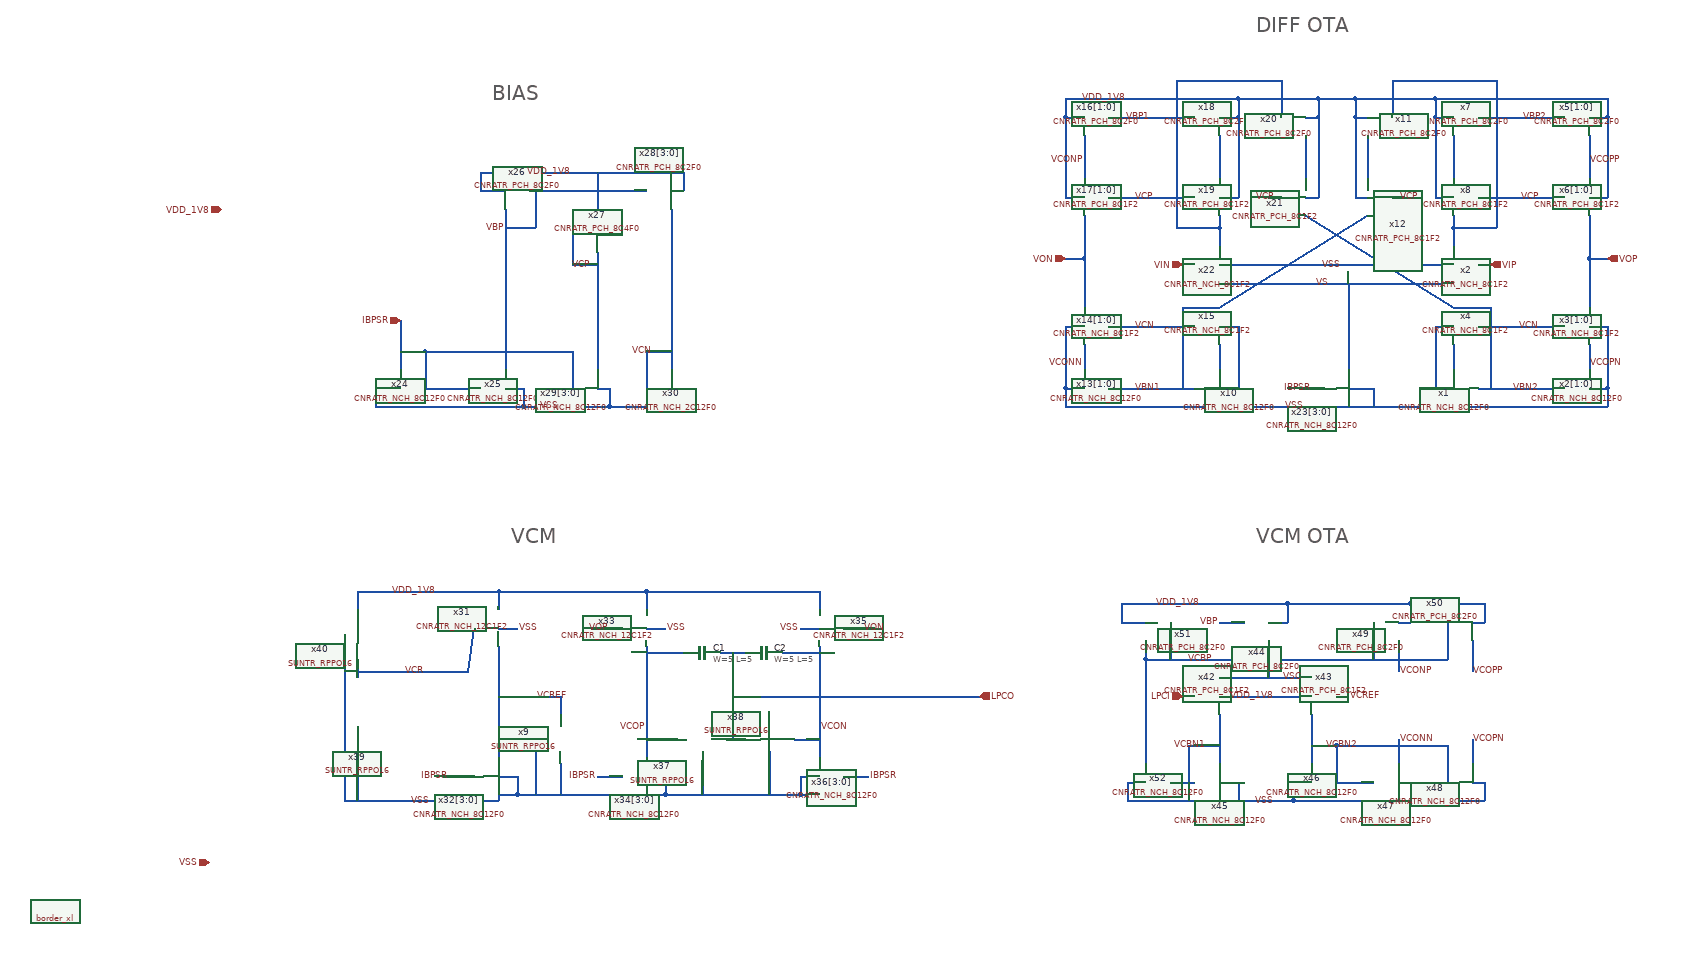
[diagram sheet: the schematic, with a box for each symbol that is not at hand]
v {xschem version=3.4.4 file_version=1.2
}
G {}
K {}
V {}
S {}
E {}
T {DIFF OTA} 1830 -1450 0 0 1 1 {}
T {BIAS} 590 -1340 0 0 1 1 {}
T {VCM} 620 -620 0 0 1 1 {}
T {VCM OTA} 1830 -620 0 0 1 1 {}
N 2120 -1290 2150 -1290 {
lab=VDD_1V8}
N 2120 -1320 2120 -1290 {
lab=VDD_1V8}
N 2120 -1320 2150 -1320 {
lab=VDD_1V8}
N 2370 -1290 2400 -1290 {
lab=VDD_1V8}
N 2400 -1320 2400 -1290 {
lab=VDD_1V8}
N 2370 -1320 2400 -1320 {
lab=VDD_1V8}
N 2370 -1260 2370 -1190 {
lab=VCOPP}
N 2150 -1260 2150 -1190 {
lab=#net1}
N 2120 -1160 2150 -1160 {
lab=VDD_1V8}
N 2120 -1290 2120 -1160 {
lab=VDD_1V8}
N 2370 -1160 2400 -1160 {
lab=VDD_1V8}
N 2400 -1290 2400 -1160 {
lab=VDD_1V8}
N 2150 -920 2150 -880 {
lab=#net2}
N 2120 -950 2150 -950 {
lab=VSS}
N 2120 -950 2120 -820 {
lab=VSS}
N 2120 -820 2150 -820 {
lab=VSS}
N 2120 -850 2150 -850 {
lab=VSS}
N 2370 -850 2400 -850 {
lab=VSS}
N 2400 -850 2400 -820 {
lab=VSS}
N 2370 -820 2400 -820 {
lab=VSS}
N 2370 -920 2370 -880 {
lab=VCOPN}
N 2370 -950 2400 -950 {
lab=VSS}
N 2400 -950 2400 -850 {
lab=VSS}
N 2150 -1320 2370 -1320 {
lab=VDD_1V8}
N 2190 -850 2330 -850 {
lab=VBN2}
N 2190 -1290 2330 -1290 {
lab=VBP2}
N 2150 -1130 2150 -1110 {
lab=VBP2}
N 2150 -980 2210 -980 {
lab=VBN2}
N 2210 -980 2210 -850 {
lab=VBN2}
N 2150 -820 2370 -820 {
lab=VSS}
N 2010 -1320 2120 -1320 {
lab=VDD_1V8}
N 1990 -1320 2010 -1320 {
lab=VDD_1V8}
N 1990 -1320 1990 -1290 {
lab=VDD_1V8}
N 1990 -1290 2010 -1290 {
lab=VDD_1V8}
N 1990 -1290 1990 -1160 {
lab=VDD_1V8}
N 1990 -1160 2010 -1160 {
lab=VDD_1V8}
N 2010 -1260 2010 -1190 {
lab=#net3}
N 2190 -1160 2330 -1160 {
lab=VCP}
N 2190 -950 2330 -950 {
lab=VCN}
N 1990 -820 2010 -820 {
lab=VSS}
N 2150 -1110 2150 -1080 {
lab=VBP2}
N 2010 -820 2120 -820 {
lab=VSS}
N 2220 -1290 2220 -1230 {
lab=VBP2}
N 2220 -1230 2220 -1110 {
lab=VBP2}
N 2150 -1110 2220 -1110 {
lab=VBP2}
N 2050 -1350 2050 -1290 {
lab=VBP2}
N 2050 -1350 2220 -1350 {
lab=VBP2}
N 2220 -1350 2220 -1290 {
lab=VBP2}
N 2050 -1160 2070 -1160 {
lab=VCP}
N 1990 -1020 2150 -1020 {
lab=VS}
N 1770 -1290 1800 -1290 {
lab=VDD_1V8}
N 1800 -1320 1800 -1290 {
lab=VDD_1V8}
N 1770 -1320 1800 -1320 {
lab=VDD_1V8}
N 1520 -1290 1550 -1290 {
lab=VDD_1V8}
N 1520 -1320 1520 -1290 {
lab=VDD_1V8}
N 1520 -1320 1550 -1320 {
lab=VDD_1V8}
N 1550 -1260 1550 -1190 {
lab=VCONP}
N 1770 -1260 1770 -1190 {
lab=#net4}
N 1770 -1160 1800 -1160 {
lab=VDD_1V8}
N 1800 -1290 1800 -1160 {
lab=VDD_1V8}
N 1520 -1160 1550 -1160 {
lab=VDD_1V8}
N 1520 -1290 1520 -1160 {
lab=VDD_1V8}
N 1770 -920 1770 -880 {
lab=#net5}
N 1770 -950 1800 -950 {
lab=VSS}
N 1800 -950 1800 -820 {
lab=VSS}
N 1770 -820 1800 -820 {
lab=VSS}
N 1770 -850 1800 -850 {
lab=VSS}
N 1520 -850 1550 -850 {
lab=VSS}
N 1520 -850 1520 -820 {
lab=VSS}
N 1520 -820 1550 -820 {
lab=VSS}
N 1550 -920 1550 -880 {
lab=VCONN}
N 1520 -950 1550 -950 {
lab=VSS}
N 1520 -950 1520 -850 {
lab=VSS}
N 1550 -1320 1770 -1320 {
lab=VDD_1V8}
N 1590 -850 1730 -850 {
lab=VBN1}
N 1590 -1290 1730 -1290 {
lab=VBP1}
N 1770 -1130 1770 -1110 {
lab=VBP1}
N 1710 -980 1770 -980 {
lab=VBN1}
N 1710 -980 1710 -850 {
lab=VBN1}
N 1550 -820 1770 -820 {
lab=VSS}
N 1800 -1320 1910 -1320 {
lab=VDD_1V8}
N 1910 -1320 1930 -1320 {
lab=VDD_1V8}
N 1930 -1320 1930 -1290 {
lab=VDD_1V8}
N 1910 -1290 1930 -1290 {
lab=VDD_1V8}
N 1930 -1290 1930 -1160 {
lab=VDD_1V8}
N 1910 -1160 1930 -1160 {
lab=VDD_1V8}
N 1910 -1260 1910 -1190 {
lab=#net6}
N 1590 -1160 1730 -1160 {
lab=VCP}
N 1590 -950 1730 -950 {
lab=VCN}
N 1910 -820 1930 -820 {
lab=VSS}
N 1770 -1110 1770 -1080 {
lab=VBP1}
N 1800 -820 1910 -820 {
lab=VSS}
N 1700 -1290 1700 -1230 {
lab=VBP1}
N 1700 -1230 1700 -1110 {
lab=VBP1}
N 1700 -1110 1770 -1110 {
lab=VBP1}
N 1870 -1350 1870 -1290 {
lab=VBP1}
N 1700 -1350 1870 -1350 {
lab=VBP1}
N 1700 -1350 1700 -1290 {
lab=VBP1}
N 1850 -1160 1870 -1160 {
lab=VCP}
N 1770 -1020 1930 -1020 {
lab=VS}
N 1930 -820 1990 -820 {
lab=VSS}
N 1930 -1020 1990 -1020 {
lab=VS}
N 1770 -1050 2150 -1050 {
lab=VSS}
N 1980 -850 2020 -850 {
lab=VSS}
N 2020 -850 2020 -820 {
lab=VSS}
N 1980 -1020 1980 -880 {
lab=VS}
N 1930 -1320 1990 -1320 {
lab=VDD_1V8}
N 1900 -850 1940 -850 {
lab=IBPSR}
N 1710 -1050 1730 -1050 {
lab=VIN}
N 2190 -1050 2210 -1050 {
lab=VIP}
N 2370 -1060 2400 -1060 {
lab=VOP}
N 1520 -1060 1550 -1060 {
lab=VON}
N 440 -960 440 -880 {
lab=IBPSR}
N 400 -850 440 -850 {
lab=VSS}
N 400 -850 400 -820 {
lab=VSS}
N 400 -820 440 -820 {
lab=VSS}
N 480 -910 480 -850 {
lab=IBPSR}
N 440 -910 480 -910 {
lab=IBPSR}
N 480 -850 570 -850 {
lab=IBPSR}
N 610 -1030 610 -880 {
lab=VBP}
N 610 -1140 610 -1030 {
lab=VBP}
N 570 -1170 610 -1170 {
lab=VDD_1V8}
N 570 -1200 570 -1170 {
lab=VDD_1V8}
N 570 -1200 610 -1200 {
lab=VDD_1V8}
N 610 -1200 880 -1200 {
lab=VDD_1V8}
N 880 -1170 900 -1170 {
lab=VDD_1V8}
N 900 -1200 900 -1170 {
lab=VDD_1V8}
N 880 -1200 900 -1200 {
lab=VDD_1V8}
N 650 -1170 840 -1170 {
lab=VBP}
N 610 -1110 660 -1110 {
lab=VBP}
N 660 -1170 660 -1110 {
lab=VBP}
N 760 -1070 760 -880 {
lab=VCP}
N 480 -910 720 -910 {
lab=IBPSR}
N 720 -910 720 -850 {
lab=IBPSR}
N 610 -850 640 -850 {
lab=VSS}
N 640 -850 640 -820 {
lab=VSS}
N 610 -820 640 -820 {
lab=VSS}
N 440 -820 610 -820 {
lab=VSS}
N 640 -820 760 -820 {
lab=VSS}
N 760 -850 780 -850 {
lab=VSS}
N 780 -850 780 -820 {
lab=VSS}
N 760 -820 780 -820 {
lab=VSS}
N 760 -1100 790 -1100 {
lab=VDD_1V8}
N 790 -1130 790 -1100 {
lab=VDD_1V8}
N 760 -1130 790 -1130 {
lab=VDD_1V8}
N 760 -1200 760 -1130 {
lab=VDD_1V8}
N 880 -1140 880 -880 {
lab=VCN}
N 880 -850 900 -850 {
lab=VSS}
N 900 -850 900 -820 {
lab=VSS}
N 880 -820 900 -820 {
lab=VSS}
N 780 -820 880 -820 {
lab=VSS}
N 840 -910 840 -850 {
lab=VCN}
N 840 -910 880 -910 {
lab=VCN}
N 720 -1100 720 -1050 {
lab=VCP}
N 720 -1050 760 -1050 {
lab=VCP}
N 600 -430 600 -250 {
lab=VCREF}
N 600 -220 630 -220 {
lab=VSS}
N 630 -220 630 -190 {
lab=VSS}
N 600 -190 630 -190 {
lab=VSS}
N 600 -460 630 -460 {
lab=VSS}
N 600 -520 600 -490 {
lab=VDD_1V8}
N 600 -520 630 -520 {
lab=VDD_1V8}
N 840 -430 840 -250 {
lab=VCOP}
N 840 -220 870 -220 {
lab=VSS}
N 870 -220 870 -190 {
lab=VSS}
N 840 -190 870 -190 {
lab=VSS}
N 840 -460 870 -460 {
lab=VSS}
N 840 -520 840 -490 {
lab=VDD_1V8}
N 840 -520 870 -520 {
lab=VDD_1V8}
N 1120 -430 1120 -250 {
lab=VCON}
N 1090 -220 1120 -220 {
lab=VSS}
N 1090 -220 1090 -190 {
lab=VSS}
N 1090 -190 1120 -190 {
lab=VSS}
N 1090 -460 1120 -460 {
lab=VSS}
N 1120 -520 1120 -490 {
lab=VDD_1V8}
N 1090 -520 1120 -520 {
lab=VDD_1V8}
N 980 -280 1000 -280 {
lab=LPCO}
N 970 -280 980 -280 {
lab=LPCO}
N 960 -420 1000 -420 {
lab=LPCO}
N 980 -420 980 -280 {
lab=LPCO}
N 840 -420 900 -420 {
lab=VCOP}
N 840 -280 890 -280 {
lab=VCOP}
N 1080 -280 1120 -280 {
lab=VCON}
N 1060 -420 1120 -420 {
lab=VCON}
N 870 -520 1090 -520 {
lab=VDD_1V8}
N 630 -520 840 -520 {
lab=VDD_1V8}
N 760 -220 800 -220 {
lab=IBPSR}
N 510 -220 560 -220 {
lab=IBPSR}
N 1160 -220 1200 -220 {
lab=IBPSR}
N 870 -190 1090 -190 {
lab=VSS}
N 630 -190 840 -190 {
lab=VSS}
N 930 -260 930 -190 {
lab=VSS}
N 1040 -260 1040 -190 {
lab=VSS}
N 350 -450 350 -340 {
lab=VSS}
N 350 -340 350 -180 {
lab=VSS}
N 350 -180 600 -180 {
lab=VSS}
N 600 -190 600 -180 {
lab=VSS}
N 370 -410 370 -380 {
lab=VCR}
N 370 -520 370 -490 {
lab=VDD_1V8}
N 370 -520 600 -520 {
lab=VDD_1V8}
N 370 -300 370 -180 {
lab=VSS}
N 370 -390 550 -390 {
lab=VCR}
N 550 -390 560 -460 {
lab=VCR}
N 600 -350 670 -350 {
lab=VCREF}
N 750 -460 800 -460 {
lab=VOP}
N 1160 -460 1210 -460 {
lab=VON}
N 2060 -470 2080 -470 {
lab=VDD_1V8}
N 2080 -500 2080 -470 {
lab=VDD_1V8}
N 2060 -500 2080 -500 {
lab=VDD_1V8}
N 2180 -470 2200 -470 {
lab=VDD_1V8}
N 2200 -500 2200 -470 {
lab=VDD_1V8}
N 2180 -500 2200 -500 {
lab=VDD_1V8}
N 2080 -500 2180 -500 {
lab=VDD_1V8}
N 2180 -210 2200 -210 {
lab=VSS}
N 2200 -210 2200 -180 {
lab=VSS}
N 2180 -180 2200 -180 {
lab=VSS}
N 2060 -180 2180 -180 {
lab=VSS}
N 2060 -210 2080 -210 {
lab=VSS}
N 2080 -210 2080 -180 {
lab=VSS}
N 1890 -210 1920 -210 {
lab=VSS}
N 1890 -210 1890 -180 {
lab=VSS}
N 1890 -180 1920 -180 {
lab=VSS}
N 1920 -180 2060 -180 {
lab=VSS}
N 1770 -180 1890 -180 {
lab=VSS}
N 1770 -210 1800 -210 {
lab=VSS}
N 1800 -210 1800 -180 {
lab=VSS}
N 1770 -320 1770 -240 {
lab=VCBN1}
N 1920 -320 1920 -240 {
lab=VCBN2}
N 1920 -270 1960 -270 {
lab=VCBN2}
N 1960 -270 1960 -210 {
lab=VCBN2}
N 1960 -210 2020 -210 {
lab=VCBN2}
N 1960 -270 2140 -270 {
lab=VCBN2}
N 2140 -270 2140 -210 {
lab=VCBN2}
N 1650 -440 1650 -410 {
lab=VCBP}
N 1650 -410 2140 -410 {
lab=VCBP}
N 2140 -470 2140 -410 {
lab=VCBP}
N 2020 -470 2020 -410 {
lab=VCBP}
N 1650 -410 1650 -240 {
lab=VCBP}
N 1690 -210 1730 -210 {
lab=VCBN1}
N 1720 -270 1770 -270 {
lab=VCBN1}
N 1720 -270 1720 -210 {
lab=VCBN1}
N 1650 -180 1770 -180 {
lab=VSS}
N 1620 -210 1650 -210 {
lab=VSS}
N 1620 -210 1620 -180 {
lab=VSS}
N 1620 -180 1650 -180 {
lab=VSS}
N 1610 -470 1650 -470 {
lab=VDD_1V8}
N 1610 -500 1610 -470 {
lab=VDD_1V8}
N 1610 -500 1650 -500 {
lab=VDD_1V8}
N 1690 -470 1690 -410 {
lab=VCBP}
N 1770 -380 1920 -380 {
lab=VSC}
N 1770 -350 1920 -350 {
lab=VDD_1V8}
N 1850 -440 1850 -380 {
lab=VSC}
N 1850 -470 1880 -470 {
lab=VDD_1V8}
N 1880 -500 1880 -470 {
lab=VDD_1V8}
N 1850 -500 1880 -500 {
lab=VDD_1V8}
N 1880 -500 2060 -500 {
lab=VDD_1V8}
N 1650 -500 1850 -500 {
lab=VDD_1V8}
N 1960 -350 1980 -350 {
lab=VCREF}
N 1710 -350 1730 -350 {
lab=LPCI}
N 2060 -440 2060 -390 {
lab=VCONP}
N 2180 -440 2180 -390 {
lab=VCOPP}
N 2060 -280 2060 -240 {
lab=VCONN}
N 2180 -280 2180 -240 {
lab=VCOPN}
N 1770 -470 1810 -470 {
lab=VBP}
N 1770 -980 2010 -1130 {
lab=VBN1}
N 1910 -1130 2150 -980 {
lab=VBN2}
N 700 -350 700 -320 {
lab=VCREF}
N 670 -350 700 -350 {
lab=VCREF}
N 660 -280 680 -280 {
lab=VSS}
N 660 -280 660 -190 {
lab=VSS}
N 700 -240 700 -190 {
lab=VSS}
N 1550 -1060 1550 -980 {
lab=VON}
N 2370 -1060 2370 -980 {
lab=VOP}
N 1550 -1130 1550 -1060 {
lab=VON}
N 2370 -1130 2370 -1060 {
lab=VOP}
N 980 -350 1380 -350 {
lab=LPCO}
C {devices/ipin.sym} 150 -1140 0 0 {name=p1 lab=VDD_1V8}
C {devices/ipin.sym} 130 -80 0 0 {name=p2 lab=VSS}
C {devices/ipin.sym} 1710 -1050 0 0 {name=p3 lab=VIN}
C {CNR_ATR_SKY130NM/CNRATR_NCH_8C12F0.sym} 2190 -850 0 1 {name=x1 }
C {CNR_ATR_SKY130NM/CNRATR_NCH_8C12F0.sym} 2330 -850 0 0 {name=x2[1:0]}
C {CNR_ATR_SKY130NM/CNRATR_NCH_8C1F2.sym} 2330 -950 0 0 {name=x3[1:0]}
C {CNR_ATR_SKY130NM/CNRATR_NCH_8C1F2.sym} 2190 -950 0 1 {name=x4 }
C {CNR_ATR_SKY130NM/CNRATR_PCH_8C2F0.sym} 2330 -1290 0 0 {name=x5[1:0]}
C {CNR_ATR_SKY130NM/CNRATR_PCH_8C1F2.sym} 2330 -1160 0 0 {name=x6[1:0]}
C {CNR_ATR_SKY130NM/CNRATR_PCH_8C2F0.sym} 2190 -1290 0 1 {name=x7 }
C {CNR_ATR_SKY130NM/CNRATR_PCH_8C1F2.sym} 2190 -1160 0 1 {name=x8 }
C {CNR_ATR_SKY130NM/CNRATR_PCH_8C2F0.sym} 2050 -1290 0 1 {name=x11 }
C {CNR_ATR_SKY130NM/CNRATR_PCH_8C1F2.sym} 2050 -1160 0 1 {name=x12 }
C {CNR_ATR_SKY130NM/CNRATR_NCH_8C1F2.sym} 2190 -1050 0 1 {name=x2}
C {devices/lab_wire.sym} 2290 -1160 0 0 {name=p6 sig_type=std_logic lab=VCP}
C {devices/lab_wire.sym} 2060 -1160 0 1 {name=p5 sig_type=std_logic lab=VCP}
C {devices/lab_wire.sym} 2260 -1290 0 1 {name=p7 sig_type=std_logic lab=VBP2}
C {devices/lab_wire.sym} 2370 -1220 0 1 {name=p8 sig_type=std_logic lab=VCOPP}
C {devices/lab_wire.sym} 2370 -890 0 1 {name=p9 sig_type=std_logic lab=VCOPN}
C {devices/lab_wire.sym} 2290 -950 0 0 {name=p4 sig_type=std_logic lab=VCN}
C {devices/lab_wire.sym} 2290 -850 0 0 {name=p10 sig_type=std_logic lab=VBN2
}
C {CNR_ATR_SKY130NM/CNRATR_NCH_8C12F0.sym} 1730 -850 0 0 {name=x10 }
C {CNR_ATR_SKY130NM/CNRATR_NCH_8C12F0.sym} 1590 -850 0 1 {name=x13[1:0]}
C {CNR_ATR_SKY130NM/CNRATR_NCH_8C1F2.sym} 1590 -950 0 1 {name=x14[1:0]}
C {CNR_ATR_SKY130NM/CNRATR_NCH_8C1F2.sym} 1730 -950 0 0 {name=x15 }
C {CNR_ATR_SKY130NM/CNRATR_PCH_8C2F0.sym} 1590 -1290 0 1 {name=x16[1:0]}
C {CNR_ATR_SKY130NM/CNRATR_PCH_8C1F2.sym} 1590 -1160 0 1 {name=x17[1:0]}
C {CNR_ATR_SKY130NM/CNRATR_PCH_8C2F0.sym} 1730 -1290 0 0 {name=x18 }
C {CNR_ATR_SKY130NM/CNRATR_PCH_8C1F2.sym} 1730 -1160 0 0 {name=x19 }
C {CNR_ATR_SKY130NM/CNRATR_PCH_8C2F0.sym} 1870 -1290 0 0 {name=x20 }
C {CNR_ATR_SKY130NM/CNRATR_PCH_8C1F2.sym} 1870 -1160 0 0 {name=x21 }
C {CNR_ATR_SKY130NM/CNRATR_NCH_8C1F2.sym} 1730 -1050 0 0 {name=x22}
C {devices/lab_wire.sym} 1630 -1160 0 1 {name=p11 sig_type=std_logic lab=VCP}
C {devices/lab_wire.sym} 1860 -1160 0 0 {name=p12 sig_type=std_logic lab=VCP}
C {devices/lab_wire.sym} 1660 -1290 0 0 {name=p13 sig_type=std_logic lab=VBP1}
C {devices/lab_wire.sym} 1550 -1220 0 0 {name=p14 sig_type=std_logic lab=VCONP}
C {devices/lab_wire.sym} 1550 -890 0 0 {name=p15 sig_type=std_logic lab=VCONN}
C {devices/lab_wire.sym} 1630 -950 0 1 {name=p16 sig_type=std_logic lab=VCN}
C {devices/lab_wire.sym} 1630 -850 0 1 {name=p17 sig_type=std_logic lab=VBN1
}
C {CNR_ATR_SKY130NM/CNRATR_NCH_8C12F0.sym} 1940 -850 0 0 {name=x23[3:0]}
C {devices/lab_wire.sym} 1620 -1320 0 0 {name=p18 sig_type=std_logic lab=VDD_1V8}
C {devices/lab_wire.sym} 1910 -820 0 0 {name=p19 sig_type=std_logic lab=VSS}
C {devices/lab_wire.sym} 1920 -850 0 0 {name=p20 sig_type=std_logic lab=IBPSR
}
C {devices/ipin.sym} 2210 -1050 0 1 {name=p21 lab=VIP}
C {devices/opin.sym} 2400 -1060 0 0 {name=p22 lab=VOP}
C {devices/opin.sym} 1520 -1060 0 1 {name=p23 lab=VON}
C {CNR_ATR_SKY130NM/CNRATR_NCH_8C12F0.sym} 480 -850 0 1 {name=x24 }
C {devices/ipin.sym} 440 -960 0 0 {name=p24 lab=IBPSR
}
C {CNR_ATR_SKY130NM/CNRATR_NCH_8C12F0.sym} 570 -850 0 0 {name=x25 }
C {CNR_ATR_SKY130NM/CNRATR_PCH_8C2F0.sym} 650 -1170 0 1 {name=x26 }
C {CNR_ATR_SKY130NM/CNRATR_PCH_8C4F0.sym} 720 -1100 0 0 {name=x27 }
C {CNR_ATR_SKY130NM/CNRATR_PCH_8C2F0.sym} 840 -1170 0 0 {name=x28[3:0]}
C {CNR_ATR_SKY130NM/CNRATR_NCH_8C12F0.sym} 720 -850 0 0 {name=x29[3:0]}
C {CNR_ATR_SKY130NM/CNRATR_NCH_2C12F0.sym} 840 -850 0 0 {name=x30 }
C {devices/lab_wire.sym} 850 -910 0 0 {name=p25 sig_type=std_logic lab=VCN}
C {devices/lab_wire.sym} 750 -1050 0 0 {name=p26 sig_type=std_logic lab=VCP}
C {CNR_ATR_SKY130NM/CNRATR_NCH_12C1F2.sym} 560 -460 0 0 {name=x31 }
C {CNR_ATR_SKY130NM/CNRATR_NCH_8C12F0.sym} 560 -220 0 0 {name=x32[3:0]}
C {CNR_ATR_SKY130NM/CNRATR_NCH_12C1F2.sym} 800 -460 0 0 {name=x33 }
C {CNR_ATR_SKY130NM/CNRATR_NCH_8C12F0.sym} 800 -220 0 0 {name=x34[3:0]}
C {CNR_ATR_SKY130NM/CNRATR_NCH_12C1F2.sym} 1160 -460 0 1 {name=x35 }
C {CNR_ATR_SKY130NM/CNRATR_NCH_8C12F0.sym} 1160 -220 0 1 {name=x36[3:0]}
C {sky130_fd_pr/cap_mim_m3_1.sym} 930 -420 1 0 {name=C1 model=cap_mim_m3_1 W=5 L=5 MF=1 spiceprefix=X}
C {sky130_fd_pr/cap_mim_m3_1.sym} 1030 -420 1 0 {name=C2 model=cap_mim_m3_1 W=5 L=5 MF=1 spiceprefix=X}
C {SUN_TR_SKY130NM/SUNTR_RPPO16.sym} 890 -280 0 0 {name=x37 }
C {SUN_TR_SKY130NM/SUNTR_RPPO16.sym} 1000 -280 0 0 {name=x38 }
C {devices/lab_wire.sym} 520 -220 0 0 {name=p27 sig_type=std_logic lab=IBPSR
}
C {devices/lab_wire.sym} 760 -220 0 0 {name=p28 sig_type=std_logic lab=IBPSR
}
C {devices/lab_wire.sym} 1200 -220 0 1 {name=p29 sig_type=std_logic lab=IBPSR
}
C {SUN_TR_SKY130NM/SUNTR_RPPO16.sym} 370 -300 1 1 {name=x39 }
C {SUN_TR_SKY130NM/SUNTR_RPPO16.sym} 370 -410 1 1 {name=x40 }
C {devices/lab_wire.sym} 660 -350 0 1 {name=p30 sig_type=std_logic lab=VCREF
}
C {devices/lab_wire.sym} 720 -1200 0 0 {name=p32 sig_type=std_logic lab=VDD_1V8}
C {devices/lab_wire.sym} 500 -520 0 0 {name=p33 sig_type=std_logic lab=VDD_1V8}
C {devices/lab_wire.sym} 490 -180 0 0 {name=p34 sig_type=std_logic lab=VSS}
C {devices/lab_wire.sym} 700 -820 0 0 {name=p35 sig_type=std_logic lab=VSS}
C {devices/lab_wire.sym} 780 -460 0 0 {name=p36 sig_type=std_logic lab=VOP
}
C {devices/lab_wire.sym} 1190 -460 0 1 {name=p37 sig_type=std_logic lab=VON
}
C {CNR_ATR_SKY130NM/CNRATR_PCH_8C1F2.sym} 1730 -350 0 0 {name=x42 }
C {CNR_ATR_SKY130NM/CNRATR_PCH_8C1F2.sym} 1960 -350 0 1 {name=x43 }
C {devices/lab_wire.sym} 610 -1110 0 0 {name=p38 sig_type=std_logic lab=VBP}
C {CNR_ATR_SKY130NM/CNRATR_PCH_8C2F0.sym} 1810 -470 0 0 {name=x44 }
C {CNR_ATR_SKY130NM/CNRATR_NCH_8C12F0.sym} 1730 -210 0 0 {name=x45 }
C {CNR_ATR_SKY130NM/CNRATR_NCH_8C12F0.sym} 1960 -210 0 1 {name=x46 }
C {CNR_ATR_SKY130NM/CNRATR_NCH_8C12F0.sym} 2020 -210 0 0 {name=x47 }
C {CNR_ATR_SKY130NM/CNRATR_NCH_8C12F0.sym} 2140 -210 0 0 {name=x48 }
C {CNR_ATR_SKY130NM/CNRATR_PCH_8C2F0.sym} 2020 -470 0 0 {name=x49 }
C {CNR_ATR_SKY130NM/CNRATR_PCH_8C2F0.sym} 2140 -470 0 0 {name=x50 }
C {CNR_ATR_SKY130NM/CNRATR_PCH_8C2F0.sym} 1690 -470 0 1 {name=x51 }
C {CNR_ATR_SKY130NM/CNRATR_NCH_8C12F0.sym} 1690 -210 0 1 {name=x52 }
C {devices/lab_wire.sym} 1740 -500 0 0 {name=p39 sig_type=std_logic lab=VDD_1V8}
C {devices/lab_wire.sym} 1860 -180 0 0 {name=p40 sig_type=std_logic lab=VSS}
C {devices/lab_wire.sym} 1980 -350 0 1 {name=p42 sig_type=std_logic lab=VCREF
}
C {devices/lab_wire.sym} 1860 -350 0 0 {name=p43 sig_type=std_logic lab=VDD_1V8
}
C {cborder/border_xl.sym} -120 0 0 0 {}
C {devices/lab_wire.sym} 1970 -1050 0 0 {name=p48 sig_type=std_logic lab=VSS}
C {devices/lab_wire.sym} 1950 -1020 0 0 {name=p49 sig_type=std_logic lab=VS}
C {devices/lab_wire.sym} 1760 -410 0 0 {name=p50 sig_type=std_logic lab=VCBP
}
C {devices/lab_wire.sym} 1870 -380 0 1 {name=p51 sig_type=std_logic lab=VSC
}
C {devices/lab_wire.sym} 1770 -470 0 0 {name=p52 sig_type=std_logic lab=VBP
}
C {SUN_TR_SKY130NM/SUNTR_RPPO16.sym} 700 -320 1 0 {name=x9 }
C {devices/ipin.sym} 1710 -350 0 0 {name=p53 lab=LPCI}
C {devices/opin.sym} 1380 -350 0 0 {name=p54 lab=LPCO}
C {devices/lab_wire.sym} 1940 -270 0 1 {name=p31 sig_type=std_logic lab=VCBN2
}
C {devices/lab_wire.sym} 1750 -270 0 0 {name=p41 sig_type=std_logic lab=VCBN1
}
C {devices/lab_wire.sym} 1120 -300 0 1 {name=p55 sig_type=std_logic lab=VCON
}
C {devices/lab_wire.sym} 840 -300 0 0 {name=p56 sig_type=std_logic lab=VCOP
}
C {devices/lab_wire.sym} 480 -390 0 0 {name=p57 sig_type=std_logic lab=VCR
}
C {devices/lab_wire.sym} 2180 -390 0 1 {name=p44 sig_type=std_logic lab=VCOPP}
C {devices/lab_wire.sym} 2060 -390 0 1 {name=p45 sig_type=std_logic lab=VCONP}
C {devices/lab_wire.sym} 2060 -280 0 1 {name=p46 sig_type=std_logic lab=VCONN}
C {devices/lab_wire.sym} 2180 -280 0 1 {name=p47 sig_type=std_logic lab=VCOPN}
C {devices/lab_wire.sym} 630 -460 0 1 {name=p58 sig_type=std_logic lab=VSS}
C {devices/lab_wire.sym} 870 -460 0 1 {name=p59 sig_type=std_logic lab=VSS}
C {devices/lab_wire.sym} 1090 -460 0 0 {name=p60 sig_type=std_logic lab=VSS}
